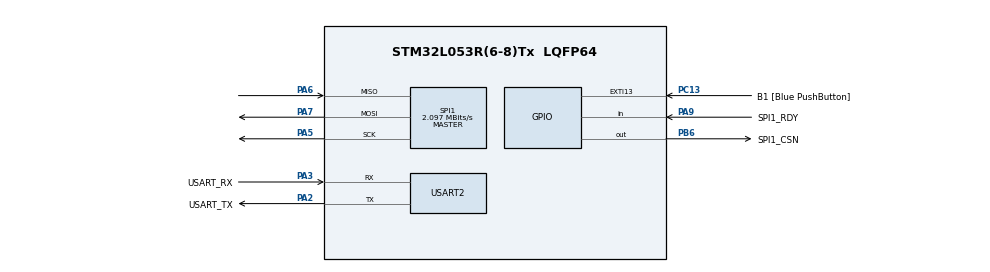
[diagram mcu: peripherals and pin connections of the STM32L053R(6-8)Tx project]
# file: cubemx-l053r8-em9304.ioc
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Dma.Request0=SPI1_RX
Dma.Request1=SPI1_TX
Dma.SPI1_RX.0.Direction=DMA_PERIPH_TO_MEMORY
Dma.SPI1_RX.0.Instance=DMA1_Channel2
Dma.SPI1_RX.0.MemDataAlignment=DMA_MDATAALIGN_BYTE
Dma.SPI1_RX.0.MemInc=DMA_MINC_ENABLE
Dma.SPI1_RX.0.Mode=DMA_NORMAL
Dma.SPI1_RX.0.PeriphDataAlignment=DMA_PDATAALIGN_BYTE
Dma.SPI1_RX.0.PeriphInc=DMA_PINC_DISABLE
Dma.SPI1_RX.0.Priority=DMA_PRIORITY_LOW
Dma.SPI1_TX.1.Direction=DMA_MEMORY_TO_PERIPH
Dma.SPI1_TX.1.Instance=DMA1_Channel3
Dma.SPI1_TX.1.MemDataAlignment=DMA_MDATAALIGN_BYTE
Dma.SPI1_TX.1.MemInc=DMA_MINC_ENABLE
Dma.SPI1_TX.1.Mode=DMA_NORMAL
Dma.SPI1_TX.1.PeriphDataAlignment=DMA_PDATAALIGN_BYTE
Dma.SPI1_TX.1.PeriphInc=DMA_PINC_DISABLE
Dma.SPI1_TX.1.Priority=DMA_PRIORITY_LOW
Mcu.Family=STM32L0
Mcu.Name=STM32L053R(6-8)Tx
Mcu.Package=LQFP64
NVIC.DMA1_Channel2_3_IRQn=true\:0\:0\:false\:false\:true
NVIC.SPI1_IRQn=true\:0\:0\:false\:false\:true
PA13.GPIO_Label=TMS
PA13.Signal=SYS_SWDIO
PA14.GPIO_Label=TCK
PA14.Signal=SYS_SWCLK
PA2.GPIO_Label=USART_TX
PA2.Mode=Asynchronous
PA2.Signal=USART2_TX
PA3.GPIO_Label=USART_RX
PA3.Mode=Asynchronous
PA3.Signal=USART2_RX
PA5.Mode=Full_Duplex_Master
PA5.Signal=SPI1_SCK
PA6.Mode=Full_Duplex_Master
PA6.Signal=SPI1_MISO
PA7.Mode=Full_Duplex_Master
PA7.Signal=SPI1_MOSI
PA9.GPIO_Label=SPI1_RDY
PA9.Signal=GPIO_Input
PB6.GPIO_Label=SPI1_CSN
PB6.Signal=GPIO_Output
PC13.GPIO_Label=B1 [Blue PushButton]
PC13.GPIO_ModeDefaultEXTI=GPIO_MODE_IT_FALLING
PC13.Signal=GPXTI13
PC14-OSC32_IN.Signal=RCC_OSC32_IN
PC15-OSC32_OUT.Signal=RCC_OSC32_OUT
PH0-OSC_IN.Signal=RCC_OSC_IN
PH1-OSC_OUT.Signal=RCC_OSC_OUT
ProjectManager.HeapSize=0x200
ProjectManager.StackSize=0x400
ProjectManager.TargetToolchain=Makefile
RCC.AHBFreq_Value=4194000
RCC.APB1Freq_Value=4194000
RCC.APB1TimFreq_Value=4194000
RCC.APB2Freq_Value=4194000
RCC.APB2TimFreq_Value=4194000
RCC.HCLKFreq_Value=4194000
RCC.HSE_VALUE=8000000
RCC.HSI16_VALUE=16000000
RCC.HSI48_VALUE=48000000
RCC.HSI_VALUE=16000000
RCC.LSEState=RCC_LSE_ON
RCC.LSE_VALUE=32768
RCC.MSIClockRange=RCC_MSIRANGE_6
RCC.MSI_VALUE=4194000
RCC.SYSCLKFreq_VALUE=4194000
RCC.VCOOutputFreq_Value=48000000
SPI1.CalculateBaudRate=2.097 MBits/s
SPI1.Direction=SPI_DIRECTION_2LINES
SPI1.Mode=SPI_MODE_MASTER
SPI1.VirtualType=VM_MASTER
USART2.VirtualMode-Asynchronous=VM_ASYNC
USART2.WordLength=WORDLENGTH_8B
board=NUCLEO-L053R8

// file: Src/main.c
/**
  ******************************************************************************
  * File Name          : main.c
  * Description        : Main program body
  ******************************************************************************
  ** This notice applies to any and all portions of this file
  * that are not between comment pairs USER CODE BEGIN and
  * USER CODE END. Other portions of this file, whether
  * inserted by the user or by software development tools
  * are owned by their respective copyright owners.
  *
  * COPYRIGHT(c) 2017 STMicroelectronics
  *
  * Redistribution and use in source and binary forms, with or without modification,
  * are permitted provided that the following conditions are met:
  *   1. Redistributions of source code must retain the above copyright notice,
  *      this list of conditions and the following disclaimer.
  *   2. Redistributions in binary form must reproduce the above copyright notice,
  *      this list of conditions and the following disclaimer in the documentation
  *      and/or other materials provided with the distribution.
  *   3. Neither the name of STMicroelectronics nor the names of its contributors
  *      may be used to endorse or promote products derived from this software
  *      without specific prior written permission.
  *
  * THIS SOFTWARE IS PROVIDED BY THE COPYRIGHT HOLDERS AND CONTRIBUTORS "AS IS"
  * AND ANY EXPRESS OR IMPLIED WARRANTIES, INCLUDING, BUT NOT LIMITED TO, THE
  * IMPLIED WARRANTIES OF MERCHANTABILITY AND FITNESS FOR A PARTICULAR PURPOSE ARE
  * DISCLAIMED. IN NO EVENT SHALL THE COPYRIGHT HOLDER OR CONTRIBUTORS BE LIABLE
  * FOR ANY DIRECT, INDIRECT, INCIDENTAL, SPECIAL, EXEMPLARY, OR CONSEQUENTIAL
  * DAMAGES (INCLUDING, BUT NOT LIMITED TO, PROCUREMENT OF SUBSTITUTE GOODS OR
  * SERVICES; LOSS OF USE, DATA, OR PROFITS; OR BUSINESS INTERRUPTION) HOWEVER
  * CAUSED AND ON ANY THEORY OF LIABILITY, WHETHER IN CONTRACT, STRICT LIABILITY,
  * OR TORT (INCLUDING NEGLIGENCE OR OTHERWISE) ARISING IN ANY WAY OUT OF THE USE
  * OF THIS SOFTWARE, EVEN IF ADVISED OF THE POSSIBILITY OF SUCH DAMAGE.
  *
  ******************************************************************************
  */
#include "main.h"
#include "stm32l0xx_hal.h"

/* USER CODE BEGIN Includes */
#include "port.h"
/* USER CODE END Includes */

SPI_HandleTypeDef hspi1;
DMA_HandleTypeDef hdma_spi1_rx;
DMA_HandleTypeDef hdma_spi1_tx;

UART_HandleTypeDef huart2;

/* USER CODE BEGIN PV */
/* Private variables ---------------------------------------------------------*/

/* USER CODE END PV */

void SystemClock_Config(void);
static void MX_GPIO_Init(void);
static void MX_DMA_Init(void);
static void MX_SPI1_Init(void);
static void MX_USART2_UART_Init(void);

/* USER CODE BEGIN PFP */
/* Private function prototypes -----------------------------------------------*/

/* USER CODE END PFP */

int main(void)
{

  /* MCU Configuration----------------------------------------------------------*/

  /* Reset of all peripherals, Initializes the Flash interface and the Systick. */
  HAL_Init();

  /* Configure the system clock */
  SystemClock_Config();

  /* Initialize all configured peripherals */
  MX_GPIO_Init();
  MX_DMA_Init();
  MX_SPI1_Init();
  MX_USART2_UART_Init();

  /* Infinite loop */
  /* USER CODE BEGIN WHILE */
  port_main();
  while (1)
  {
  /* USER CODE END WHILE */

  }

}

/** System Clock Configuration
*/
void SystemClock_Config(void)
{

  RCC_OscInitTypeDef RCC_OscInitStruct;
  RCC_ClkInitTypeDef RCC_ClkInitStruct;
  RCC_PeriphCLKInitTypeDef PeriphClkInit;

    /**Configure the main internal regulator output voltage
    */
  __HAL_PWR_VOLTAGESCALING_CONFIG(PWR_REGULATOR_VOLTAGE_SCALE1);

    /**Initializes the CPU, AHB and APB busses clocks
    */
  RCC_OscInitStruct.OscillatorType = RCC_OSCILLATORTYPE_HSI;
  RCC_OscInitStruct.HSIState = RCC_HSI_ON;
  RCC_OscInitStruct.HSICalibrationValue = 16;
  RCC_OscInitStruct.PLL.PLLState = RCC_PLL_ON;
  RCC_OscInitStruct.PLL.PLLSource = RCC_PLLSOURCE_HSI;
  RCC_OscInitStruct.PLL.PLLMUL = RCC_PLLMUL_4;
  RCC_OscInitStruct.PLL.PLLDIV = RCC_PLLDIV_2;
  if (HAL_RCC_OscConfig(&RCC_OscInitStruct) != HAL_OK)
  {
    _Error_Handler(__FILE__, __LINE__);
  }

    /**Initializes the CPU, AHB and APB busses clocks
    */
  RCC_ClkInitStruct.ClockType = RCC_CLOCKTYPE_HCLK|RCC_CLOCKTYPE_SYSCLK
                              |RCC_CLOCKTYPE_PCLK1|RCC_CLOCKTYPE_PCLK2;
  RCC_ClkInitStruct.SYSCLKSource = RCC_SYSCLKSOURCE_PLLCLK;
  RCC_ClkInitStruct.AHBCLKDivider = RCC_SYSCLK_DIV1;
  RCC_ClkInitStruct.APB1CLKDivider = RCC_HCLK_DIV1;
  RCC_ClkInitStruct.APB2CLKDivider = RCC_HCLK_DIV1;

  if (HAL_RCC_ClockConfig(&RCC_ClkInitStruct, FLASH_LATENCY_1) != HAL_OK)
  {
    _Error_Handler(__FILE__, __LINE__);
  }

  PeriphClkInit.PeriphClockSelection = RCC_PERIPHCLK_USART2;
  PeriphClkInit.Usart2ClockSelection = RCC_USART2CLKSOURCE_PCLK1;
  if (HAL_RCCEx_PeriphCLKConfig(&PeriphClkInit) != HAL_OK)
  {
    _Error_Handler(__FILE__, __LINE__);
  }

    /**Configure the Systick interrupt time
    */
  HAL_SYSTICK_Config(HAL_RCC_GetHCLKFreq()/1000);

    /**Configure the Systick
    */
  HAL_SYSTICK_CLKSourceConfig(SYSTICK_CLKSOURCE_HCLK);

  /* SysTick_IRQn interrupt configuration */
  HAL_NVIC_SetPriority(SysTick_IRQn, 0, 0);
}

/* SPI1 init function */
static void MX_SPI1_Init(void)
{

  hspi1.Instance = SPI1;
  hspi1.Init.Mode = SPI_MODE_MASTER;
  hspi1.Init.Direction = SPI_DIRECTION_2LINES;
  hspi1.Init.DataSize = SPI_DATASIZE_8BIT;
  hspi1.Init.CLKPolarity = SPI_POLARITY_LOW;
  hspi1.Init.CLKPhase = SPI_PHASE_1EDGE;
  hspi1.Init.NSS = SPI_NSS_SOFT;
  hspi1.Init.BaudRatePrescaler = SPI_BAUDRATEPRESCALER_4;
  hspi1.Init.FirstBit = SPI_FIRSTBIT_MSB;
  hspi1.Init.TIMode = SPI_TIMODE_DISABLE;
  hspi1.Init.CRCCalculation = SPI_CRCCALCULATION_DISABLE;
  hspi1.Init.CRCPolynomial = 7;
  if (HAL_SPI_Init(&hspi1) != HAL_OK)
  {
    _Error_Handler(__FILE__, __LINE__);
  }

}

/* USART2 init function */
static void MX_USART2_UART_Init(void)
{

  huart2.Instance = USART2;
  huart2.Init.BaudRate = 115200;
  huart2.Init.WordLength = UART_WORDLENGTH_8B;
  huart2.Init.StopBits = UART_STOPBITS_1;
  huart2.Init.Parity = UART_PARITY_NONE;
  huart2.Init.Mode = UART_MODE_TX_RX;
  huart2.Init.HwFlowCtl = UART_HWCONTROL_NONE;
  huart2.Init.OverSampling = UART_OVERSAMPLING_16;
  huart2.Init.OneBitSampling = UART_ONE_BIT_SAMPLE_DISABLE;
  huart2.AdvancedInit.AdvFeatureInit = UART_ADVFEATURE_NO_INIT;
  if (HAL_UART_Init(&huart2) != HAL_OK)
  {
    _Error_Handler(__FILE__, __LINE__);
  }

}

static void MX_DMA_Init(void)
{
  /* DMA controller clock enable */
  __HAL_RCC_DMA1_CLK_ENABLE();

  /* DMA interrupt init */
  /* DMA1_Channel2_3_IRQn interrupt configuration */
  HAL_NVIC_SetPriority(DMA1_Channel2_3_IRQn, 0, 0);
  HAL_NVIC_EnableIRQ(DMA1_Channel2_3_IRQn);

}

/** Configure pins as
        * Analog
        * Input
        * Output
        * EVENT_OUT
        * EXTI
*/
static void MX_GPIO_Init(void)
{

  GPIO_InitTypeDef GPIO_InitStruct;

  /* GPIO Ports Clock Enable */
  __HAL_RCC_GPIOC_CLK_ENABLE();
  __HAL_RCC_GPIOH_CLK_ENABLE();
  __HAL_RCC_GPIOA_CLK_ENABLE();
  __HAL_RCC_GPIOB_CLK_ENABLE();

  /*Configure GPIO pin Output Level */
  HAL_GPIO_WritePin(DEBUG_0_GPIO_Port, DEBUG_0_Pin, GPIO_PIN_RESET);

  /*Configure GPIO pin Output Level */
  HAL_GPIO_WritePin(EN_GPIO_Port, EN_Pin, GPIO_PIN_RESET);

  /*Configure GPIO pin Output Level */
  HAL_GPIO_WritePin(SPI1_CSN_GPIO_Port, SPI1_CSN_Pin, GPIO_PIN_SET);

  /*Configure GPIO pin : B1_Pin */
  GPIO_InitStruct.Pin = B1_Pin;
  GPIO_InitStruct.Mode = GPIO_MODE_IT_FALLING;
  GPIO_InitStruct.Pull = GPIO_NOPULL;
  HAL_GPIO_Init(B1_GPIO_Port, &GPIO_InitStruct);

  /*Configure GPIO pin : DEBUG_0_Pin */
  GPIO_InitStruct.Pin = DEBUG_0_Pin;
  GPIO_InitStruct.Mode = GPIO_MODE_OUTPUT_PP;
  GPIO_InitStruct.Pull = GPIO_NOPULL;
  GPIO_InitStruct.Speed = GPIO_SPEED_FREQ_LOW;
  HAL_GPIO_Init(DEBUG_0_GPIO_Port, &GPIO_InitStruct);

  /*Configure GPIO pins : EN_Pin SPI1_CSN_Pin */
  GPIO_InitStruct.Pin = EN_Pin|SPI1_CSN_Pin;
  GPIO_InitStruct.Mode = GPIO_MODE_OUTPUT_PP;
  GPIO_InitStruct.Pull = GPIO_NOPULL;
  GPIO_InitStruct.Speed = GPIO_SPEED_FREQ_LOW;
  HAL_GPIO_Init(GPIOB, &GPIO_InitStruct);

  /*Configure GPIO pin : SPI1_RDY_Pin */
  GPIO_InitStruct.Pin = SPI1_RDY_Pin;
  GPIO_InitStruct.Mode = GPIO_MODE_IT_RISING;
  GPIO_InitStruct.Pull = GPIO_NOPULL;
  HAL_GPIO_Init(SPI1_RDY_GPIO_Port, &GPIO_InitStruct);

  /* EXTI interrupt init*/
  HAL_NVIC_SetPriority(EXTI4_15_IRQn, 0, 0);
  HAL_NVIC_EnableIRQ(EXTI4_15_IRQn);

}

void _Error_Handler(char * file, int line)
{
  while(1)
  {
  }
}

/************************ (C) COPYRIGHT STMicroelectronics *****END OF FILE****/
